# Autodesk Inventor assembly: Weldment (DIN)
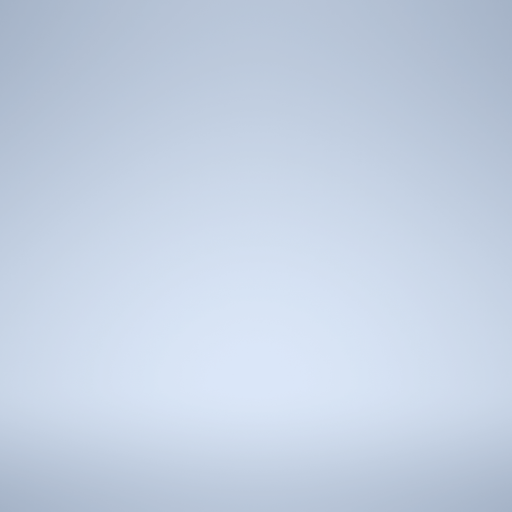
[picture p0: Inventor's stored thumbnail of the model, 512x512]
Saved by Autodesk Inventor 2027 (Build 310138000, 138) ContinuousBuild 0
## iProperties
Length Units: 11269
Angle Units: 11283
Time Units: 11279
Mass Units: 11290
Length Display Precision: 3
Angle Display Precision: 2
Part Number: Weldment (DIN)
Document SubType Name: Weldment
Created: 2002-06
Designer: smithga
Shininess: 64.0
Angle Units: 11279
Time Units: 11290
Mass Units: 11283
Compacted: True
Created: 2002-08
Weld Material: Welded Aluminum-6061
Density: 0.0
Volumn: 0.0
Area: 0.0
PropertySet Name: Model Information
Control State: 0
Master: False
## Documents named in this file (1)
- D:\AUTOBUILD\inventor\Application\App\Templates\en-US\Metric\Weldment (DIN).iam
